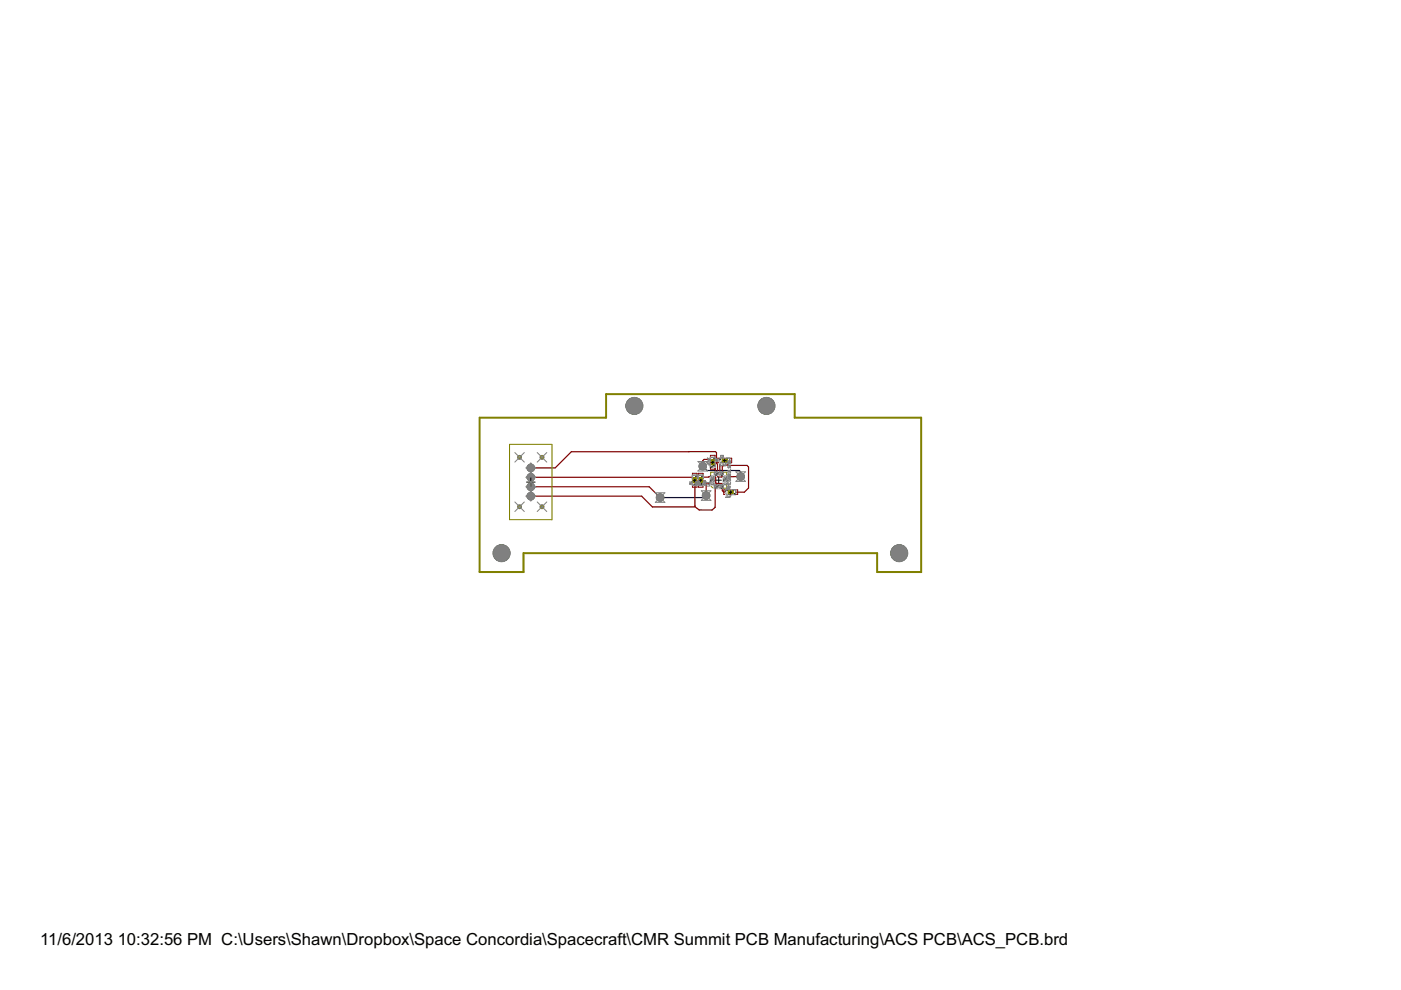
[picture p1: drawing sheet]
<svg xmlns="http://www.w3.org/2000/svg" width="297mm" height="210mm" viewBox="0 0 297 210" stroke-linecap="round" stroke-linejoin="round" font-family="sans-serif">
<defs><g id="words">
<g font-size="4">
<text x="8.5" y="200.4">11/6/2013</text>
<text x="25" y="200.4">10:32:56 PM C:\Users\Shawn\Dropbox\Space Concordia\Spacecraft\CMR Summit PCB Manufacturing\ACS PCB\ACS_PCB.brd</text>
</g>
</g></defs>
<g fill="#808080" stroke="#808080" stroke-width=".21">
<circle cx="112.5" cy="101.2" r=".8"/>
<circle cx="112.5" cy="103.2" r=".8"/>
<circle cx="112.5" cy="105.2" r=".8"/>
<circle cx="112.5" cy="99.2" r=".8"/>
<circle cx="114.9" cy="107.4" r=".4"/>
<circle cx="110.2" cy="107.4" r=".4"/>
<circle cx="110.2" cy="97" r=".4"/>
<circle cx="114.9" cy="97" r=".4"/>
<circle cx="140" cy="105.5" r=".8"/>
<circle cx="149.7" cy="105.1" r=".8"/>
<circle cx="157" cy="101" r=".8"/>
<circle cx="149" cy="98.8" r=".8"/>
<circle cx="106.3" cy="117.3" r="1.8"/>
<circle cx="134.5" cy="86.1" r="1.8"/>
<circle cx="162.5" cy="86.1" r="1.8"/>
<circle cx="190.6" cy="117.3" r="1.8"/>
</g>
<path d="M149 98.8l.9 1h6.8l.3 .3v.9M149.7 105.1l-.4 .4h-9.3" fill="none" stroke="#000080" stroke-width=".25"/>
<circle cx="112.5" cy="101.2" r=".7" fill="#008000" stroke="#008000" stroke-width=".21"/>
<circle cx="112.5" cy="101.2" r=".4" fill="#fff" stroke="#000" stroke-width=".21"/>
<circle cx="112.5" cy="103.2" r=".7" fill="#008000" stroke="#008000" stroke-width=".21"/>
<circle cx="112.5" cy="103.2" r=".4" fill="#fff" stroke="#000" stroke-width=".21"/>
<circle cx="112.5" cy="105.2" r=".7" fill="#008000" stroke="#008000" stroke-width=".21"/>
<circle cx="112.5" cy="105.2" r=".4" fill="#fff" stroke="#000" stroke-width=".21"/>
<circle cx="112.5" cy="99.2" r=".7" fill="#008000" stroke="#008000" stroke-width=".21"/>
<circle cx="112.5" cy="99.2" r=".4" fill="#fff" stroke="#000" stroke-width=".21"/>
<circle cx="140" cy="105.5" r=".7" fill="#008000" stroke="#008000" stroke-width=".21"/>
<circle cx="140" cy="105.5" r=".44" fill="#fff" stroke="#000" stroke-width=".21"/>
<circle cx="149.7" cy="105.1" r=".7" fill="#008000" stroke="#008000" stroke-width=".21"/>
<circle cx="149.7" cy="105.1" r=".44" fill="#fff" stroke="#000" stroke-width=".21"/>
<circle cx="157" cy="101" r=".7" fill="#008000" stroke="#008000" stroke-width=".21"/>
<circle cx="157" cy="101" r=".44" fill="#fff" stroke="#000" stroke-width=".21"/>
<circle cx="149" cy="98.8" r=".7" fill="#008000" stroke="#008000" stroke-width=".21"/>
<circle cx="149" cy="98.8" r=".44" fill="#fff" stroke="#000" stroke-width=".21"/>
<circle cx="106.3" cy="117.3" r="1.71" fill="#008000" stroke="#008000" stroke-width=".21"/>
<circle cx="106.3" cy="117.3" r="1.21" fill="#fff" stroke="#000" stroke-width=".21"/>
<circle cx="134.5" cy="86.1" r="1.71" fill="#008000" stroke="#008000" stroke-width=".21"/>
<circle cx="134.5" cy="86.1" r="1.21" fill="#fff" stroke="#000" stroke-width=".21"/>
<circle cx="162.5" cy="86.1" r="1.71" fill="#008000" stroke="#008000" stroke-width=".21"/>
<circle cx="162.5" cy="86.1" r="1.21" fill="#fff" stroke="#000" stroke-width=".21"/>
<circle cx="190.6" cy="117.3" r="1.71" fill="#008000" stroke="#008000" stroke-width=".21"/>
<circle cx="190.6" cy="117.3" r="1.21" fill="#fff" stroke="#000" stroke-width=".21"/>
<g fill="#800000" stroke="#800000" stroke-width=".21">
<path d="M153 102.9h.3v.6h-.3z"/>
<path d="M152.5 102.9h.3v.6h-.3z"/>
<path d="M152 102.9h.3v.6h-.3z"/>
<path d="M151.5 102.9h.3v.6h-.3z"/>
<path d="M153.4 102.4h.7v.3h-.7z"/>
<path d="M150.7 101.9h.6v.3h-.6z"/>
<path d="M150.7 101.4h.6v.3h-.6z"/>
<path d="M150.7 100.9h.6v.3h-.6z"/>
<path d="M151.5 100.1h.3v.7h-.3z"/>
<path d="M152 100.1h.3v.7h-.3z"/>
<path d="M152.5 100.1h.3v.7h-.3z"/>
<path d="M153 100.1h.3v.7h-.3z"/>
<path d="M153.4 101.9h.7v.3h-.7z"/>
<path d="M153.4 100.9h.7v.3h-.7z"/>
<path d="M150.7 102.4h.6v.3h-.6z"/>
<path d="M153.4 101.4h.7v.3h-.7z"/>
<path d="M153.9 103.9h.7v.9h-.7z"/>
<path d="M155.2 103.9h.7v.9h-.7z"/>
<path d="M150.7 97h.9v.7h-.9z"/>
<path d="M150.7 98.3h.9v.7h-.9z"/>
<path d="M152.6 97.2h.8v.9h-.8z"/>
<path d="M153.9 97.2h.8v.9h-.8z"/>
<path d="M146.9 102.1h.8v.7h-.8z"/>
<path d="M146.9 100.8h.8v.7h-.8z"/>
<path d="M148.1 102.1h.9v.7h-.9z"/>
<path d="M148.1 100.8h.9v.7h-.9z"/>
</g>
<g fill="none" stroke="#800000" stroke-width=".25">
<path d="M146.1 95.8h.1M151.1 97.4h-1.8l-.3 .3v1.1M151.1 98.7l.5 .5v1.2M153 97.6l-.4 .4v2.4M154.2 98.6l-.7 .1-.4 .3v2l-.1 .1h-.7h-.2v-2.7l-.2-.2v-2.2l-.2-.2h-30.6l-3.4 3.4h-5.2M154.2 98.6l4.2 .1 .3 .3v4.5l-.9 .9h-2.2M154.3 97.6l-.1 1M112.5 101.2h34.8l4.3-.2 .1 .3v1.1l1.4 .2v1.4l.3 .3 .9 .1M112.5 105.2h23.5l2.3 2.3h8.9l.1-.2M112.5 103.2h25.1l2.4 2.3M147.3 102.5v4.9l1 .7h2.7l.6-.5v-4.4M148.6 102.5l2.4 .1"/>
<path d="M149.9 102.5l-.2 .1v2.5M151 101v.1M152.2 102.5l-.1 .7M153.8 101h3.2"/>
</g>
<circle cx="112.5" cy="101.2" r=".7" fill="#008000" stroke="#008000" stroke-width=".21"/>
<circle cx="112.5" cy="101.2" r=".4" fill="#fff" stroke="#000" stroke-width=".21"/>
<circle cx="112.5" cy="103.2" r=".7" fill="#008000" stroke="#008000" stroke-width=".21"/>
<circle cx="112.5" cy="103.2" r=".4" fill="#fff" stroke="#000" stroke-width=".21"/>
<circle cx="112.5" cy="105.2" r=".7" fill="#008000" stroke="#008000" stroke-width=".21"/>
<circle cx="112.5" cy="105.2" r=".4" fill="#fff" stroke="#000" stroke-width=".21"/>
<circle cx="112.5" cy="99.2" r=".7" fill="#008000" stroke="#008000" stroke-width=".21"/>
<circle cx="112.5" cy="99.2" r=".4" fill="#fff" stroke="#000" stroke-width=".21"/>
<circle cx="140" cy="105.5" r=".7" fill="#008000" stroke="#008000" stroke-width=".21"/>
<circle cx="140" cy="105.5" r=".44" fill="#fff" stroke="#000" stroke-width=".21"/>
<circle cx="149.7" cy="105.1" r=".7" fill="#008000" stroke="#008000" stroke-width=".21"/>
<circle cx="149.7" cy="105.1" r=".44" fill="#fff" stroke="#000" stroke-width=".21"/>
<circle cx="157" cy="101" r=".7" fill="#008000" stroke="#008000" stroke-width=".21"/>
<circle cx="157" cy="101" r=".44" fill="#fff" stroke="#000" stroke-width=".21"/>
<circle cx="149" cy="98.8" r=".7" fill="#008000" stroke="#008000" stroke-width=".21"/>
<circle cx="149" cy="98.8" r=".44" fill="#fff" stroke="#000" stroke-width=".21"/>
<circle cx="106.3" cy="117.3" r="1.71" fill="#008000" stroke="#008000" stroke-width=".21"/>
<circle cx="106.3" cy="117.3" r="1.21" fill="#fff" stroke="#000" stroke-width=".21"/>
<circle cx="134.5" cy="86.1" r="1.71" fill="#008000" stroke="#008000" stroke-width=".21"/>
<circle cx="134.5" cy="86.1" r="1.21" fill="#fff" stroke="#000" stroke-width=".21"/>
<circle cx="162.5" cy="86.1" r="1.71" fill="#008000" stroke="#008000" stroke-width=".21"/>
<circle cx="162.5" cy="86.1" r="1.21" fill="#fff" stroke="#000" stroke-width=".21"/>
<circle cx="190.6" cy="117.3" r="1.71" fill="#008000" stroke="#008000" stroke-width=".21"/>
<circle cx="190.6" cy="117.3" r="1.21" fill="#fff" stroke="#000" stroke-width=".21"/>
<path d="M150.6 96.5h1v3h-1zM152.2 97.2h2.9v.9h-2.9zM146.8 100.4h1v2.9h-1zM148.1 100.4h1v2.9h-1zM153.5 103.9h2.9v.9h-2.9z" fill="none" stroke="#800000" stroke-width=".21"/>
<g fill="#808080" stroke="#808080" stroke-width=".21">
<path d="M152.9 102.8h.5v.8h-.5z"/>
<path d="M152.4 102.8h.5v.8h-.5z"/>
<path d="M151.9 102.8h.5v.8h-.5z"/>
<path d="M151.4 102.8h.5v.8h-.5z"/>
<path d="M153.3 102.3h.9v.5h-.9z"/>
<path d="M150.6 101.8h.8v.5h-.8z"/>
<path d="M150.6 101.3h.8v.5h-.8z"/>
<path d="M150.6 100.8h.8v.5h-.8z"/>
<path d="M151.4 100h.5v.9h-.5z"/>
<path d="M151.9 100h.5v.9h-.5z"/>
<path d="M152.4 100h.5v.9h-.5z"/>
<path d="M152.9 100h.5v.9h-.5z"/>
<path d="M153.3 101.8h.9v.5h-.9z"/>
<path d="M153.3 100.8h.9v.5h-.9z"/>
<path d="M150.6 102.3h.8v.5h-.8z"/>
<path d="M153.3 101.3h.9v.5h-.9z"/>
<path d="M153.8 103.8h.9v1.1h-.9z"/>
<path d="M155.1 103.8h.9v1.1h-.9z"/>
<path d="M150.6 96.9h1.1v.9h-1.1z"/>
<path d="M150.6 98.2h1.1v.9h-1.1z"/>
<path d="M152.5 97.1h.9v1.1h-.9z"/>
<path d="M153.9 97.1h.8v1.1h-.8z"/>
<path d="M146.7 102h1.1v.9h-1.1z"/>
<path d="M146.7 100.7h1.1v.9h-1.1z"/>
<path d="M148 102h1.1v.9h-1.1z"/>
<path d="M148 100.7h1.1v.9h-1.1z"/>
<path d="M153 102.9h.3v.6h-.3z"/>
<path d="M152.5 102.9h.3v.6h-.3z"/>
<path d="M152 102.9h.3v.6h-.3z"/>
<path d="M151.5 102.9h.3v.6h-.3z"/>
<path d="M153.4 102.4h.7v.3h-.7z"/>
<path d="M150.7 101.9h.6v.3h-.6z"/>
<path d="M150.7 101.4h.6v.3h-.6z"/>
<path d="M150.7 100.9h.6v.3h-.6z"/>
<path d="M151.5 100.1h.3v.7h-.3z"/>
<path d="M152 100.1h.3v.7h-.3z"/>
<path d="M152.5 100.1h.3v.7h-.3z"/>
<path d="M153 100.1h.3v.7h-.3z"/>
<path d="M153.4 101.9h.7v.3h-.7z"/>
<path d="M153.4 100.9h.7v.3h-.7z"/>
<path d="M150.7 102.4h.6v.3h-.6z"/>
<path d="M153.4 101.4h.7v.3h-.7z"/>
<path d="M153.9 103.9h.7v.9h-.7z"/>
<path d="M155.2 103.9h.7v.9h-.7z"/>
<path d="M150.7 97h.9v.7h-.9z"/>
<path d="M150.7 98.3h.9v.7h-.9z"/>
<path d="M152.6 97.2h.8v.9h-.8z"/>
<path d="M153.9 97.2h.8v.9h-.8z"/>
<path d="M146.9 102.1h.8v.7h-.8z"/>
<path d="M146.9 100.8h.8v.7h-.8z"/>
<path d="M148.1 102.1h.9v.7h-.9z"/>
<path d="M148.1 100.8h.9v.7h-.9z"/>
<path d="M154.7 104.1h.4v.5h-.4z"/>
<path d="M150.8 97.8h.6v.4h-.6z"/>
<path d="M153.5 97.3h.3v.6h-.3z"/>
<path d="M147 101.6h.6v.4h-.6z"/>
<path d="M148.3 101.6h.6v.4h-.6z"/>
</g>
<g fill="#808080" stroke="#808080" stroke-width=".21">
<circle cx="112.5" cy="101.2" r=".8"/>
<circle cx="112.5" cy="103.2" r=".8"/>
<circle cx="112.5" cy="105.2" r=".8"/>
<circle cx="112.5" cy="99.2" r=".8"/>
<circle cx="114.9" cy="107.4" r=".4"/>
<circle cx="110.2" cy="107.4" r=".4"/>
<circle cx="110.2" cy="97" r=".4"/>
<circle cx="114.9" cy="97" r=".4"/>
<circle cx="140" cy="105.5" r=".8"/>
<circle cx="149.7" cy="105.1" r=".8"/>
<circle cx="157" cy="101" r=".8"/>
<circle cx="149" cy="98.8" r=".8"/>
<circle cx="106.3" cy="117.3" r="1.8"/>
<circle cx="134.5" cy="86.1" r="1.8"/>
<circle cx="162.5" cy="86.1" r="1.8"/>
<circle cx="190.6" cy="117.3" r="1.8"/>
</g>
<g fill="none" stroke="#808000" stroke-width=".21">
<path d="M108 94.2h9v16h-9zM150.9 97.8v.5M151.3 97.8v.5M153.4 97.4h.5M153.4 97.9h.5M147.1 101.6v.5M147.5 101.6v.5M148.4 101.6v.5M148.8 101.6v.5M150.7 103.1l.4 .3M151.3 100.1h-.6v.6M153.5 100.1h.6v.6"/>
<path d="M154.1 102.9v.6h-.6M154.7 104.1h.5M154.7 104.6h.5"/>
<circle cx="110.2" cy="97" r=".3"/>
<circle cx="114.9" cy="97" r=".3"/>
<circle cx="110.2" cy="107.4" r=".3"/>
<circle cx="114.9" cy="107.4" r=".3"/>
</g>
<path d="M151.1 98h.1M153.6 97.6v.1M154.9 104.3v.1M195.3 121.3h-9.3v-4h-75v4h-9.3v-32.7h26.8v-5h40v5h26.8v32.7" fill="none" stroke="#808000" stroke-width=".42"/>
<g fill="#808000" stroke="#808000" stroke-width=".21">
<path d="M146.9 101.6h.8v.4h-.8z"/>
<path d="M148.2 101.6h.7v.4h-.7z"/>
<path d="M154.4 104.1h.3v.5h-.3z"/>
<path d="M155.2 104.1h.3v.5h-.3z"/>
<path d="M150.8 97.5h.6v.2h-.6z"/>
<path d="M150.8 98.3h.6v.3h-.6z"/>
<path d="M153.1 97.3h.3v.6h-.3z"/>
<path d="M153.9 97.3h.3v.6h-.3z"/>
<path d="M147 102.1h.6v.3h-.6z"/>
<path d="M147 101.3h.6v.3h-.6z"/>
<path d="M148.3 102.1h.6v.3h-.6z"/>
<path d="M148.3 101.3h.6v.3h-.6z"/>
</g>
<g fill="none" stroke="#808080" stroke-width=".21">
<path d="M109.2 95.9l2 2.1M111.2 95.9l-2 2.1M112.5 98.2v1M112.5 98.2l1.1 1-2.1 2 2.1 2-1.1 1M112.5 98.2l-1 1 1 1M113.9 95.9l2 2.1M115.9 95.9l-2 2.1M135.5 85l-2 2.1M148 97.9h2l-2 2h2zM150 97.9l.1 .1M150 97v.3h.4M150.1 97.4h.3l-.1 .3h-.2"/>
<path d="M150.2 97.2v.1M150.3 98.6h.1M150.4 97.8v.2l-.3-.2-.1 .1M150.4 98.1v.3l-.3-.3-.1 .1 .1 .2M151.9 97.6v.3l.3-.1-.1-.2M152.2 97.2v.3l-.2-.3-.2 .1 .1 .2M152.8 98.6h-.2l.2-.2v.4M153 98.7h.1M153 96.6h-.2v.3h.2M153.1 96.6l.2-.1v.2M153.1 98.4h.3l-.3 .4M153.3 96.7h.1"/>
<path d="M153.3 96.7v.2h-.2M153.5 98.5l.1 .3h.2v-.3M153.9 98.6h.1M154.2 98.4h-.3v.4M154.4 98.8l-.1 .3 .2 .1 .3-.4v.4M154.4 97.7h.4l.1 .4h-.6zM154.9 99.4v.4h-.6M154.9 98.3h-.6l.2 .2-.2 .1h.6M163.5 85l-2 2.1M107.4 116.3l-2.1 2M109.2 106.4l2 2.1M111.2 106.4l-2 2.1"/>
<path d="M112.5 101.2v-1l1.1 1-2.1 2 2.1 2-1.1 1-1-1 1-1M112.5 102.2v1M112.5 104.2v1M113.9 106.4l2 2.1M115.9 106.4l-2 2.1M138.9 104.5h2.1l-2.1 2h2.1zM146.5 102.7v-.2l-.2-.1-.1 .3h.4M146.6 102.4l-.1 .2M146.6 102.2h-.4l.1 .1M146.6 102.1v.2M147.7 102.7v-.2l-.1-.1-.1 .3h.4M147.9 102.4l-.2 .2"/>
<path d="M147.9 102.1v.2l-.3-.2h-.1l.1 .2M148.1 102.7l.3-.1v.3h-.3zM148.1 102.3h.3l-.3 .2h.3M148.3 102.1v-.2h-.2v.2h.3M148.7 104.1h2l-2 2h2zM149.3 102.7l.3-.1 .1 .3h-.4zM149.3 102.3h.4l-.4 .2h.4M149.6 102.1l-.1-.2h-.2v.2h.4M149.9 102.7l.6 .1-.1 .3h-.5M150.5 102.1v.4M150.5 102.3h-.6l.2 .2M153.9 105.4h.1"/>
<path d="M154.1 105.5h.2M154.1 105.2l.1-.1v.4M154.3 103.3h-.2v.3h.2M154.3 103.7h.6M154.3 103.3h.6M154.3 101.6v.4h.3v-.4l.3 .1-.1 .3M154.4 103.6h.3M154.4 103.4l.1-.1v.3M154.4 105.2l.1 .3h.2v-.3M154.4 102.2v.4l.5-.1-.1-.3M154.6 100.1h-.3l.1 .2M154.6 100.1h.1"/>
<path d="M154.6 100.6v.2M154.6 101.2v.1M154.6 103.3v.4M154.6 100.6h-.3l.1 .3 .2-.1M154.6 101.2h-.3l.1 .3 .2-.2M154.6 100.1h.3l-.1 .2M154.6 100.6h.3l-.1 .3-.2-.1M154.6 101.2h.3l-.1 .3-.2-.2M154.8 105.3h.1M154.9 102.8h-.6l.2 .2-.2 .1h.6M155 105.1h-.2v.4M156 100h2.1l-2.1 2.1h2.1z"/>
<path d="M191.7 116.3l-2.1 2"/>
<circle cx="134.5" cy="86.1" r=".99"/>
<circle cx="162.5" cy="86.1" r=".99"/>
<circle cx="106.3" cy="117.3" r=".99"/>
<circle cx="190.6" cy="117.3" r=".99"/>
</g>
<g fill="none" stroke="#000" stroke-width=".21">
<path d="M150.8 98h.6M151.1 97.7v.6M153.4 97.6h.5M153.6 97.3v.6M111.6 102.2h1.9M112.5 101.3v1.8M147 101.8h.6M147.3 101.5v.6M148.3 101.8h.6M148.6 101.5v.6M151.8 101.8h1.2M152.4 101.2v1.2"/>
<path d="M154.6 104.4h.6M154.9 104.1v.5"/>
</g>
<use href="#words"/>
</svg>
